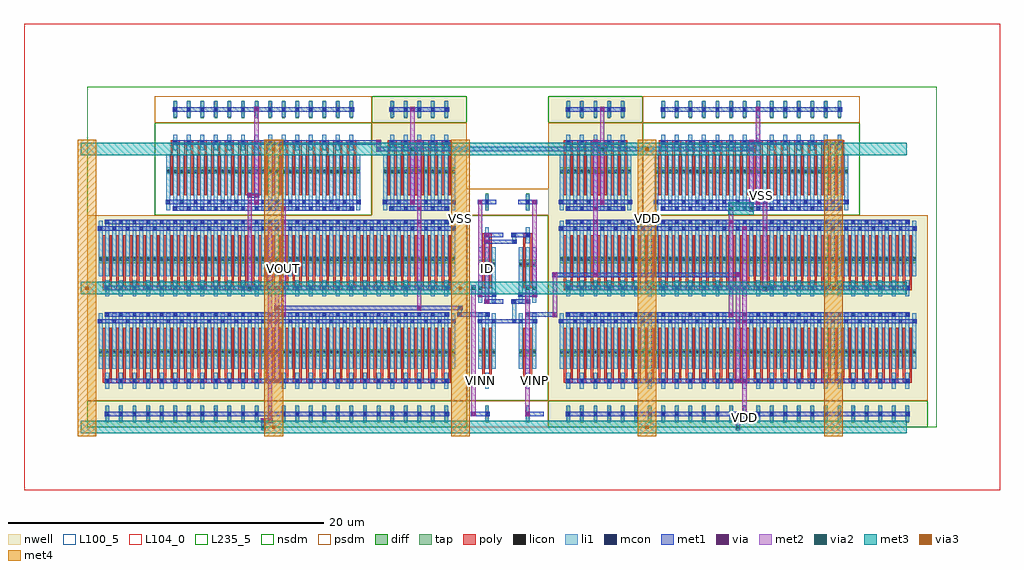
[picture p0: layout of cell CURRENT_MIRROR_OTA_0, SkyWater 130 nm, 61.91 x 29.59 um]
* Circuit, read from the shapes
.subckt CURRENT_MIRROR_OTA_0 ID VDD VINN VINP VOUT VSS
XM1 VOUT n1 VSS VSS sky130_fd_pr__nfet_01v8 w=0.42 l=0.15 m=28
XM2 n2 VINN n3 VSS sky130_fd_pr__nfet_01v8 w=0.42 l=0.15 m=2
XM3 ID ID VSS VSS sky130_fd_pr__nfet_01v8 w=0.42 l=0.15 m=2
XM4 n4 VINP n3 VSS sky130_fd_pr__nfet_01v8 w=0.42 l=0.15 m=2
XM5 n3 ID VSS VSS sky130_fd_pr__nfet_01v8 w=0.42 l=0.15 m=2
XM6 n1 n1 VSS VSS sky130_fd_pr__nfet_01v8 w=0.42 l=0.15 m=28
XM7 VOUT n2 VDD VDD sky130_fd_pr__pfet_01v8 w=0.42 l=0.15 m=104
XM8 n2 n2 VDD VDD sky130_fd_pr__pfet_01v8 w=0.42 l=0.15 m=10
XM9 n1 n4 VDD VDD sky130_fd_pr__pfet_01v8 w=0.42 l=0.15 m=104
XM10 n4 n4 VDD VDD sky130_fd_pr__pfet_01v8 w=0.42 l=0.15 m=10
.ends

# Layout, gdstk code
from math import pi, radians
import gdstk
lib = gdstk.Library(unit=1e-6, precision=1e-09)
def R(c, l, rs):  # rectangles x0, y0, x1, y1
    for r in rs: c.add(gdstk.rectangle(r[:2], r[2:], *l))
def A(c, l, x, y, w, h, nx, ny, dx, dy):  # array of equal rectangles
    R(c, l, [(x+i*dx, y+j*dy, x+i*dx+w, y+j*dy+h) for i in range(nx) for j in range(ny)])
def P(c, l, *ps):  # polygons
    for p in ps: c.add(gdstk.Polygon(p, *l))
nwell = (64, 20)
diff = (65, 20)
tap = (65, 44)
poly = (66, 20)
licon = (66, 44)
li1 = (67, 20)
mcon = (67, 44)
met1 = (68, 20)
via = (68, 44)
met2 = (69, 20)
via2 = (69, 44)
met3 = (70, 20)
via3 = (70, 44)
met4 = (71, 20)
nsdm = (93, 44)
psdm = (94, 20)
L100_5 = (100, 5)
L104_0 = (104, 0)
L235_5 = (235, 5)

dcl_nmos_s_8415993_x1_y1 = lib.new_cell('DCL_NMOS_S_8415993_X1_Y1_1730840086')
R(dcl_nmos_s_8415993_x1_y1, diff, [(0.735,2.625,1.845,3.045)])
R(dcl_nmos_s_8415993_x1_y1, tap, [(1.205,6.16,1.375,7.28)])
R(dcl_nmos_s_8415993_x1_y1, poly, [(1,1.26,1.15,4.62), (1.43,1.26,1.58,4.62), (1,4.485,1.58,4.755)])
A(dcl_nmos_s_8415993_x1_y1, licon, 0.775, 2.705, 0.17, 0.17, 3, 1, 0.43, 0)
R(dcl_nmos_s_8415993_x1_y1, licon, [(1.205,4.535,1.375,4.705), (1.205,6.635,1.375,6.805)])
A(dcl_nmos_s_8415993_x1_y1, li1, 0.735, 0.335, 0.25, 3.53, 3, 1, 0.43, 0)
R(dcl_nmos_s_8415993_x1_y1, li1, [(1.165,4.115,1.415,5.125), (1.165,6.215,1.415,7.225)])
R(dcl_nmos_s_8415993_x1_y1, mcon, [(1.205,0.335,1.375,0.505), (0.775,0.755,0.945,0.925), (1.635,0.755,1.805,0.925), (1.205,4.535,1.375,4.705), (1.205,6.635,1.375,6.805)])
R(dcl_nmos_s_8415993_x1_y1, met1, [(0.26,0.28,1.46,0.56), (0.69,0.7,1.89,0.98), (0.26,4.48,1.46,4.76), (0.69,6.58,1.89,6.86)])
R(dcl_nmos_s_8415993_x1_y1, via, [(1.215,0.345,1.365,0.495), (1.645,0.765,1.795,0.915), (1.215,4.545,1.365,4.695), (1.645,6.645,1.795,6.795)])
R(dcl_nmos_s_8415993_x1_y1, met2, [(1.15,0.26,1.43,4.78), (1.58,0.68,1.86,6.88)])
R(dcl_nmos_s_8415993_x1_y1, nsdm, [(0,0,2.58,5.88)])
R(dcl_nmos_s_8415993_x1_y1, psdm, [(0,5.88,2.58,7.56)])
R(dcl_nmos_s_8415993_x1_y1, L100_5, [(0,0,2.58,7.56)])

dcl_nmos_s_91990922_x14_ = lib.new_cell('DCL_NMOS_S_91990922_X14_Y1_1730840087')
R(dcl_nmos_s_91990922_x14_, diff, [(0.735,2.625,13.025,3.045)])
A(dcl_nmos_s_91990922_x14_, tap, 1.205, 6.16, 0.17, 1.12, 14, 1, 0.86, 0)
A(dcl_nmos_s_91990922_x14_, poly, 1, 1.26, 0.15, 3.36, 28, 1, 0.43, 0)
A(dcl_nmos_s_91990922_x14_, poly, 1, 4.485, 0.58, 0.27, 14, 1, 0.86, 0)
A(dcl_nmos_s_91990922_x14_, licon, 0.775, 2.705, 0.17, 0.17, 3, 1, 0.43, 0)
A(dcl_nmos_s_91990922_x14_, licon, 1.635, 2.705, 0.17, 0.17, 3, 1, 0.43, 0)
A(dcl_nmos_s_91990922_x14_, licon, 2.495, 2.705, 0.17, 0.17, 3, 1, 0.43, 0)
A(dcl_nmos_s_91990922_x14_, licon, 3.355, 2.705, 0.17, 0.17, 3, 1, 0.43, 0)
A(dcl_nmos_s_91990922_x14_, licon, 4.215, 2.705, 0.17, 0.17, 3, 1, 0.43, 0)
A(dcl_nmos_s_91990922_x14_, licon, 5.075, 2.705, 0.17, 0.17, 3, 1, 0.43, 0)
A(dcl_nmos_s_91990922_x14_, licon, 5.935, 2.705, 0.17, 0.17, 3, 1, 0.43, 0)
A(dcl_nmos_s_91990922_x14_, licon, 6.795, 2.705, 0.17, 0.17, 3, 1, 0.43, 0)
A(dcl_nmos_s_91990922_x14_, licon, 7.655, 2.705, 0.17, 0.17, 3, 1, 0.43, 0)
A(dcl_nmos_s_91990922_x14_, licon, 8.515, 2.705, 0.17, 0.17, 3, 1, 0.43, 0)
A(dcl_nmos_s_91990922_x14_, licon, 9.375, 2.705, 0.17, 0.17, 3, 1, 0.43, 0)
A(dcl_nmos_s_91990922_x14_, licon, 10.235, 2.705, 0.17, 0.17, 3, 1, 0.43, 0)
A(dcl_nmos_s_91990922_x14_, licon, 11.095, 2.705, 0.17, 0.17, 3, 1, 0.43, 0)
A(dcl_nmos_s_91990922_x14_, licon, 11.955, 2.705, 0.17, 0.17, 3, 1, 0.43, 0)
A(dcl_nmos_s_91990922_x14_, licon, 1.205, 4.535, 0.17, 0.17, 14, 2, 0.86, 2.1)
A(dcl_nmos_s_91990922_x14_, li1, 0.735, 0.335, 0.25, 3.53, 29, 1, 0.43, 0)
A(dcl_nmos_s_91990922_x14_, li1, 1.165, 4.115, 0.25, 1.01, 14, 2, 0.86, 2.1)
A(dcl_nmos_s_91990922_x14_, mcon, 1.205, 0.335, 0.17, 0.17, 14, 2, 0.86, 4.2)
A(dcl_nmos_s_91990922_x14_, mcon, 0.775, 0.755, 0.17, 0.17, 15, 1, 0.86, 0)
A(dcl_nmos_s_91990922_x14_, mcon, 1.205, 6.635, 0.17, 0.17, 14, 1, 0.86, 0)
R(dcl_nmos_s_91990922_x14_, met1, [(1.12,0.28,12.64,0.56), (0.69,0.7,13.07,0.98), (1.12,4.48,12.64,4.76), (1.12,6.58,12.64,6.86)])
R(dcl_nmos_s_91990922_x14_, via, [(6.805,0.345,6.955,0.495), (7.235,0.765,7.385,0.915), (6.805,4.545,6.955,4.695), (7.235,6.645,7.385,6.795)])
R(dcl_nmos_s_91990922_x14_, met2, [(6.74,0.26,7.02,4.78), (7.17,0.68,7.45,6.88)])
R(dcl_nmos_s_91990922_x14_, nsdm, [(0,0,13.76,5.88)])
R(dcl_nmos_s_91990922_x14_, psdm, [(0,5.88,13.76,7.56)])
R(dcl_nmos_s_91990922_x14_, L100_5, [(0,0,13.76,7.56)])

dcl_pmos_s_18488141_x5_y = lib.new_cell('DCL_PMOS_S_18488141_X5_Y1_1730840088')
R(dcl_pmos_s_18488141_x5_y, nwell, [(0,0,6.02,7.56)])
R(dcl_pmos_s_18488141_x5_y, diff, [(0.735,2.625,5.285,3.045)])
A(dcl_pmos_s_18488141_x5_y, tap, 1.205, 6.16, 0.17, 1.12, 5, 1, 0.86, 0)
A(dcl_pmos_s_18488141_x5_y, poly, 1, 1.26, 0.15, 3.36, 10, 1, 0.43, 0)
A(dcl_pmos_s_18488141_x5_y, poly, 1, 4.485, 0.58, 0.27, 5, 1, 0.86, 0)
A(dcl_pmos_s_18488141_x5_y, licon, 0.775, 2.705, 0.17, 0.17, 3, 1, 0.43, 0)
A(dcl_pmos_s_18488141_x5_y, licon, 1.635, 2.705, 0.17, 0.17, 3, 1, 0.43, 0)
A(dcl_pmos_s_18488141_x5_y, licon, 2.495, 2.705, 0.17, 0.17, 3, 1, 0.43, 0)
A(dcl_pmos_s_18488141_x5_y, licon, 3.355, 2.705, 0.17, 0.17, 3, 1, 0.43, 0)
A(dcl_pmos_s_18488141_x5_y, licon, 4.215, 2.705, 0.17, 0.17, 3, 1, 0.43, 0)
A(dcl_pmos_s_18488141_x5_y, licon, 1.205, 4.535, 0.17, 0.17, 5, 2, 0.86, 2.1)
A(dcl_pmos_s_18488141_x5_y, li1, 0.735, 0.335, 0.25, 3.53, 11, 1, 0.43, 0)
A(dcl_pmos_s_18488141_x5_y, li1, 1.165, 4.115, 0.25, 1.01, 5, 2, 0.86, 2.1)
A(dcl_pmos_s_18488141_x5_y, mcon, 1.205, 0.335, 0.17, 0.17, 5, 2, 0.86, 4.2)
A(dcl_pmos_s_18488141_x5_y, mcon, 0.775, 0.755, 0.17, 0.17, 6, 1, 0.86, 0)
A(dcl_pmos_s_18488141_x5_y, mcon, 1.205, 6.635, 0.17, 0.17, 5, 1, 0.86, 0)
R(dcl_pmos_s_18488141_x5_y, met1, [(1.12,0.28,4.9,0.56), (0.69,0.7,5.33,0.98), (1.12,4.48,4.9,4.76), (1.12,6.58,4.9,6.86)])
R(dcl_pmos_s_18488141_x5_y, via, [(2.935,0.345,3.085,0.495), (3.365,0.765,3.515,0.915), (2.935,4.545,3.085,4.695), (3.365,6.645,3.515,6.795)])
R(dcl_pmos_s_18488141_x5_y, met2, [(2.87,0.26,3.15,4.78), (3.3,0.68,3.58,6.88)])
R(dcl_pmos_s_18488141_x5_y, nsdm, [(0,5.88,6.02,7.56)])
R(dcl_pmos_s_18488141_x5_y, psdm, [(0,0,6.02,5.88)])
R(dcl_pmos_s_18488141_x5_y, L100_5, [(0,0,6.02,7.56)])

nmos_s_70322697_x14_y1_1 = lib.new_cell('NMOS_S_70322697_X14_Y1_1730840090')
R(nmos_s_70322697_x14_y1_1, diff, [(0.735,2.625,13.025,3.045)])
A(nmos_s_70322697_x14_y1_1, tap, 1.205, 6.16, 0.17, 1.12, 14, 1, 0.86, 0)
A(nmos_s_70322697_x14_y1_1, poly, 1, 1.26, 0.15, 3.36, 28, 1, 0.43, 0)
A(nmos_s_70322697_x14_y1_1, poly, 1, 4.485, 0.58, 0.27, 14, 1, 0.86, 0)
A(nmos_s_70322697_x14_y1_1, licon, 0.775, 2.705, 0.17, 0.17, 3, 1, 0.43, 0)
A(nmos_s_70322697_x14_y1_1, licon, 1.635, 2.705, 0.17, 0.17, 3, 1, 0.43, 0)
A(nmos_s_70322697_x14_y1_1, licon, 2.495, 2.705, 0.17, 0.17, 3, 1, 0.43, 0)
A(nmos_s_70322697_x14_y1_1, licon, 3.355, 2.705, 0.17, 0.17, 3, 1, 0.43, 0)
A(nmos_s_70322697_x14_y1_1, licon, 4.215, 2.705, 0.17, 0.17, 3, 1, 0.43, 0)
A(nmos_s_70322697_x14_y1_1, licon, 5.075, 2.705, 0.17, 0.17, 3, 1, 0.43, 0)
A(nmos_s_70322697_x14_y1_1, licon, 5.935, 2.705, 0.17, 0.17, 3, 1, 0.43, 0)
A(nmos_s_70322697_x14_y1_1, licon, 6.795, 2.705, 0.17, 0.17, 3, 1, 0.43, 0)
A(nmos_s_70322697_x14_y1_1, licon, 7.655, 2.705, 0.17, 0.17, 3, 1, 0.43, 0)
A(nmos_s_70322697_x14_y1_1, licon, 8.515, 2.705, 0.17, 0.17, 3, 1, 0.43, 0)
A(nmos_s_70322697_x14_y1_1, licon, 9.375, 2.705, 0.17, 0.17, 3, 1, 0.43, 0)
A(nmos_s_70322697_x14_y1_1, licon, 10.235, 2.705, 0.17, 0.17, 3, 1, 0.43, 0)
A(nmos_s_70322697_x14_y1_1, licon, 11.095, 2.705, 0.17, 0.17, 3, 1, 0.43, 0)
A(nmos_s_70322697_x14_y1_1, licon, 11.955, 2.705, 0.17, 0.17, 3, 1, 0.43, 0)
A(nmos_s_70322697_x14_y1_1, licon, 1.205, 4.535, 0.17, 0.17, 14, 2, 0.86, 2.1)
A(nmos_s_70322697_x14_y1_1, li1, 0.735, 0.335, 0.25, 3.53, 29, 1, 0.43, 0)
A(nmos_s_70322697_x14_y1_1, li1, 1.165, 4.115, 0.25, 1.01, 14, 2, 0.86, 2.1)
A(nmos_s_70322697_x14_y1_1, mcon, 1.205, 0.335, 0.17, 0.17, 14, 2, 0.86, 4.2)
A(nmos_s_70322697_x14_y1_1, mcon, 0.775, 0.755, 0.17, 0.17, 15, 1, 0.86, 0)
A(nmos_s_70322697_x14_y1_1, mcon, 1.205, 6.635, 0.17, 0.17, 14, 1, 0.86, 0)
R(nmos_s_70322697_x14_y1_1, met1, [(1.12,0.28,12.64,0.56), (0.69,0.7,13.07,0.98), (1.12,4.48,12.64,4.76), (1.12,6.58,12.64,6.86)])
R(nmos_s_70322697_x14_y1_1, via, [(7.235,0.765,7.385,0.915), (7.235,6.645,7.385,6.795)])
R(nmos_s_70322697_x14_y1_1, met2, [(7.17,0.68,7.45,6.88)])
R(nmos_s_70322697_x14_y1_1, nsdm, [(0,0,13.76,5.88)])
R(nmos_s_70322697_x14_y1_1, psdm, [(0,5.88,13.76,7.56)])
R(nmos_s_70322697_x14_y1_1, L100_5, [(0,0,13.76,7.56)])

nmos_s_73503000_x1_y1_17 = lib.new_cell('NMOS_S_73503000_X1_Y1_1730840091')
R(nmos_s_73503000_x1_y1_17, diff, [(0.735,2.625,1.845,3.045)])
R(nmos_s_73503000_x1_y1_17, tap, [(1.205,6.16,1.375,7.28)])
R(nmos_s_73503000_x1_y1_17, poly, [(1,1.26,1.15,4.62), (1.43,1.26,1.58,4.62), (1,4.485,1.58,4.755)])
A(nmos_s_73503000_x1_y1_17, licon, 0.775, 2.705, 0.17, 0.17, 3, 1, 0.43, 0)
R(nmos_s_73503000_x1_y1_17, licon, [(1.205,4.535,1.375,4.705), (1.205,6.635,1.375,6.805)])
A(nmos_s_73503000_x1_y1_17, li1, 0.735, 0.335, 0.25, 3.53, 3, 1, 0.43, 0)
R(nmos_s_73503000_x1_y1_17, li1, [(1.165,4.115,1.415,5.125), (1.165,6.215,1.415,7.225)])
R(nmos_s_73503000_x1_y1_17, mcon, [(1.205,0.335,1.375,0.505), (0.775,0.755,0.945,0.925), (1.635,0.755,1.805,0.925), (1.205,4.535,1.375,4.705), (1.205,6.635,1.375,6.805)])
R(nmos_s_73503000_x1_y1_17, met1, [(0.26,0.28,1.46,0.56), (0.69,0.7,1.89,0.98), (0.26,4.48,1.46,4.76), (0.69,6.58,1.89,6.86)])
R(nmos_s_73503000_x1_y1_17, via, [(1.645,0.765,1.795,0.915), (1.645,6.645,1.795,6.795)])
R(nmos_s_73503000_x1_y1_17, met2, [(1.58,0.68,1.86,6.88)])
R(nmos_s_73503000_x1_y1_17, nsdm, [(0,0,2.58,5.88)])
R(nmos_s_73503000_x1_y1_17, psdm, [(0,5.88,2.58,7.56)])
R(nmos_s_73503000_x1_y1_17, L100_5, [(0,0,2.58,7.56)])

pmos_s_55784090_x26_y2_1 = lib.new_cell('PMOS_S_55784090_X26_Y2_1730840092')
R(pmos_s_55784090_x26_y2_1, nwell, [(0,0,24.08,13.44)])
R(pmos_s_55784090_x26_y2_1, diff, [(0.735,2.625,23.345,3.045), (0.735,8.505,23.345,8.925)])
A(pmos_s_55784090_x26_y2_1, tap, 1.205, 12.04, 0.17, 1.12, 26, 1, 0.86, 0)
A(pmos_s_55784090_x26_y2_1, poly, 1, 1.26, 0.15, 3.36, 52, 2, 0.43, 5.88)
A(pmos_s_55784090_x26_y2_1, poly, 1, 4.485, 0.58, 0.27, 26, 2, 0.86, 5.88)
A(pmos_s_55784090_x26_y2_1, licon, 0.775, 2.705, 0.17, 0.17, 3, 2, 0.43, 5.88)
A(pmos_s_55784090_x26_y2_1, licon, 1.635, 2.705, 0.17, 0.17, 3, 2, 0.43, 5.88)
A(pmos_s_55784090_x26_y2_1, licon, 2.495, 2.705, 0.17, 0.17, 3, 2, 0.43, 5.88)
A(pmos_s_55784090_x26_y2_1, licon, 3.355, 2.705, 0.17, 0.17, 3, 2, 0.43, 5.88)
A(pmos_s_55784090_x26_y2_1, licon, 4.215, 2.705, 0.17, 0.17, 3, 2, 0.43, 5.88)
A(pmos_s_55784090_x26_y2_1, licon, 5.075, 2.705, 0.17, 0.17, 3, 2, 0.43, 5.88)
A(pmos_s_55784090_x26_y2_1, licon, 5.935, 2.705, 0.17, 0.17, 3, 2, 0.43, 5.88)
A(pmos_s_55784090_x26_y2_1, licon, 6.795, 2.705, 0.17, 0.17, 3, 2, 0.43, 5.88)
A(pmos_s_55784090_x26_y2_1, licon, 7.655, 2.705, 0.17, 0.17, 3, 2, 0.43, 5.88)
A(pmos_s_55784090_x26_y2_1, licon, 8.515, 2.705, 0.17, 0.17, 3, 2, 0.43, 5.88)
A(pmos_s_55784090_x26_y2_1, licon, 9.375, 2.705, 0.17, 0.17, 3, 2, 0.43, 5.88)
A(pmos_s_55784090_x26_y2_1, licon, 10.235, 2.705, 0.17, 0.17, 3, 2, 0.43, 5.88)
A(pmos_s_55784090_x26_y2_1, licon, 11.095, 2.705, 0.17, 0.17, 3, 2, 0.43, 5.88)
A(pmos_s_55784090_x26_y2_1, licon, 11.955, 2.705, 0.17, 0.17, 3, 2, 0.43, 5.88)
A(pmos_s_55784090_x26_y2_1, licon, 12.815, 2.705, 0.17, 0.17, 3, 2, 0.43, 5.88)
A(pmos_s_55784090_x26_y2_1, licon, 13.675, 2.705, 0.17, 0.17, 3, 2, 0.43, 5.88)
A(pmos_s_55784090_x26_y2_1, licon, 14.535, 2.705, 0.17, 0.17, 3, 2, 0.43, 5.88)
A(pmos_s_55784090_x26_y2_1, licon, 15.395, 2.705, 0.17, 0.17, 3, 2, 0.43, 5.88)
A(pmos_s_55784090_x26_y2_1, licon, 16.255, 2.705, 0.17, 0.17, 3, 2, 0.43, 5.88)
A(pmos_s_55784090_x26_y2_1, licon, 17.115, 2.705, 0.17, 0.17, 3, 2, 0.43, 5.88)
A(pmos_s_55784090_x26_y2_1, licon, 17.975, 2.705, 0.17, 0.17, 3, 2, 0.43, 5.88)
A(pmos_s_55784090_x26_y2_1, licon, 18.835, 2.705, 0.17, 0.17, 3, 2, 0.43, 5.88)
A(pmos_s_55784090_x26_y2_1, licon, 19.695, 2.705, 0.17, 0.17, 3, 2, 0.43, 5.88)
A(pmos_s_55784090_x26_y2_1, licon, 20.555, 2.705, 0.17, 0.17, 3, 2, 0.43, 5.88)
A(pmos_s_55784090_x26_y2_1, licon, 21.415, 2.705, 0.17, 0.17, 3, 2, 0.43, 5.88)
A(pmos_s_55784090_x26_y2_1, licon, 22.275, 2.705, 0.17, 0.17, 3, 2, 0.43, 5.88)
A(pmos_s_55784090_x26_y2_1, licon, 1.205, 4.535, 0.17, 0.17, 26, 2, 0.86, 5.88)
R(pmos_s_55784090_x26_y2_1, licon, [(1.205,12.515,1.375,12.685), (1.205,12.515,1.375,12.685), (2.065,12.515,2.235,12.685), (2.065,12.515,2.235,12.685), (2.925,12.515,3.095,12.685), (2.925,12.515,3.095,12.685), (3.785,12.515,3.955,12.685), (3.785,12.515,3.955,12.685), (4.645,12.515,4.815,12.685), (4.645,12.515,4.815,12.685), (5.505,12.515,5.675,12.685), (5.505,12.515,5.675,12.685), (6.365,12.515,6.535,12.685), (6.365,12.515,6.535,12.685), (7.225,12.515,7.395,12.685), (7.225,12.515,7.395,12.685), (8.085,12.515,8.255,12.685), (8.085,12.515,8.255,12.685), (8.945,12.515,9.115,12.685), (8.945,12.515,9.115,12.685), (9.805,12.515,9.975,12.685), (9.805,12.515,9.975,12.685), (10.665,12.515,10.835,12.685), (10.665,12.515,10.835,12.685), (11.525,12.515,11.695,12.685), (11.525,12.515,11.695,12.685), (12.385,12.515,12.555,12.685), (12.385,12.515,12.555,12.685), (13.245,12.515,13.415,12.685), (13.245,12.515,13.415,12.685), (14.105,12.515,14.275,12.685), (14.105,12.515,14.275,12.685), (14.965,12.515,15.135,12.685), (14.965,12.515,15.135,12.685), (15.825,12.515,15.995,12.685), (15.825,12.515,15.995,12.685), (16.685,12.515,16.855,12.685), (16.685,12.515,16.855,12.685), (17.545,12.515,17.715,12.685), (17.545,12.515,17.715,12.685), (18.405,12.515,18.575,12.685), (18.405,12.515,18.575,12.685), (19.265,12.515,19.435,12.685), (19.265,12.515,19.435,12.685), (20.125,12.515,20.295,12.685), (20.125,12.515,20.295,12.685), (20.985,12.515,21.155,12.685), (20.985,12.515,21.155,12.685), (21.845,12.515,22.015,12.685), (21.845,12.515,22.015,12.685), (22.705,12.515,22.875,12.685), (22.705,12.515,22.875,12.685)])
A(pmos_s_55784090_x26_y2_1, li1, 0.735, 0.335, 0.25, 3.53, 53, 2, 0.43, 5.88)
A(pmos_s_55784090_x26_y2_1, li1, 1.165, 4.115, 0.25, 1.01, 26, 2, 0.86, 5.88)
A(pmos_s_55784090_x26_y2_1, li1, 1.165, 12.095, 0.25, 1.01, 26, 1, 0.86, 0)
A(pmos_s_55784090_x26_y2_1, mcon, 1.205, 0.335, 0.17, 0.17, 26, 2, 0.86, 4.2)
A(pmos_s_55784090_x26_y2_1, mcon, 0.775, 0.755, 0.17, 0.17, 27, 2, 0.86, 5.88)
A(pmos_s_55784090_x26_y2_1, mcon, 1.205, 6.215, 0.17, 0.17, 26, 2, 0.86, 4.2)
A(pmos_s_55784090_x26_y2_1, mcon, 1.205, 12.515, 0.17, 0.17, 26, 1, 0.86, 0)
R(pmos_s_55784090_x26_y2_1, met1, [(1.12,0.28,22.96,0.56), (0.69,0.7,23.39,0.98), (1.12,4.48,22.96,4.76), (1.12,6.16,22.96,6.44), (0.69,6.58,23.39,6.86), (1.12,10.36,22.96,10.64), (1.12,12.46,22.96,12.74)])
A(pmos_s_55784090_x26_y2_1, via, 12.395, 0.765, 0.15, 0.15, 1, 3, 0, 5.88)
R(pmos_s_55784090_x26_y2_1, via, [(11.535,0.345,11.685,0.495), (11.965,4.545,12.115,4.695), (11.535,6.225,11.685,6.375), (11.965,10.425,12.115,10.575)])
R(pmos_s_55784090_x26_y2_1, met2, [(11.47,0.26,11.75,6.46), (12.33,0.68,12.61,12.76), (11.9,4.46,12.18,10.66)])
R(pmos_s_55784090_x26_y2_1, nsdm, [(0,11.76,24.08,13.44)])
R(pmos_s_55784090_x26_y2_1, psdm, [(0,0,24.08,11.76)])
R(pmos_s_55784090_x26_y2_1, L100_5, [(0,0,24.08,13.44)])

nmos_4t_9061234_x1_y1_17 = lib.new_cell('NMOS_4T_9061234_X1_Y1_1730840089')
R(nmos_4t_9061234_x1_y1_17, diff, [(0.735,2.625,1.845,3.045)])
R(nmos_4t_9061234_x1_y1_17, tap, [(1.205,6.16,1.375,7.28)])
R(nmos_4t_9061234_x1_y1_17, poly, [(1,1.26,1.15,4.62), (1.43,1.26,1.58,4.62), (1,4.485,1.58,4.755)])
A(nmos_4t_9061234_x1_y1_17, licon, 0.775, 2.705, 0.17, 0.17, 3, 1, 0.43, 0)
R(nmos_4t_9061234_x1_y1_17, licon, [(1.205,4.535,1.375,4.705), (1.205,6.635,1.375,6.805)])
A(nmos_4t_9061234_x1_y1_17, li1, 0.735, 0.335, 0.25, 3.53, 3, 1, 0.43, 0)
R(nmos_4t_9061234_x1_y1_17, li1, [(1.165,4.115,1.415,5.125), (1.165,6.215,1.415,7.225)])
R(nmos_4t_9061234_x1_y1_17, mcon, [(1.205,0.335,1.375,0.505), (0.775,0.755,0.945,0.925), (1.635,0.755,1.805,0.925), (1.205,4.535,1.375,4.705), (1.205,6.635,1.375,6.805)])
R(nmos_4t_9061234_x1_y1_17, met1, [(0.26,0.28,1.46,0.56), (0.69,0.7,1.89,0.98), (0.26,4.48,1.46,4.76), (0.26,6.58,1.46,6.86)])
R(nmos_4t_9061234_x1_y1_17, nsdm, [(0,0,2.58,5.88)])
R(nmos_4t_9061234_x1_y1_17, psdm, [(0,5.88,2.58,7.56)])
R(nmos_4t_9061234_x1_y1_17, L100_5, [(0,0,2.58,7.56)])

current_mirror_ota_0 = lib.new_cell('CURRENT_MIRROR_OTA_0')
R(current_mirror_ota_0, li1, [(26.965,6.635,27.215,6.805), (26.965,6.635,27.215,6.805), (26.965,6.72,27.215,7.98), (23.525,7.055,23.775,7.225), (23.525,7.055,23.775,7.225), (23.525,7.055,23.775,7.225), (23.525,7.055,23.775,7.225), (23.525,7.14,23.775,7.56), (23.525,7.475,23.775,7.645), (23.525,7.475,23.775,7.645), (23.525,7.475,23.775,7.645), (23.525,7.475,23.775,7.645), (26.965,7.895,27.215,8.065), (26.965,7.895,27.215,8.065), (26.965,11.675,27.215,11.845), (26.965,11.675,27.215,11.845), (26.965,11.76,27.215,12.18), (26.965,12.095,27.215,12.265), (26.965,12.095,27.215,12.265)])
R(current_mirror_ota_0, mcon, [(27.005,6.635,27.175,6.805), (27.005,6.635,27.175,6.805), (23.565,7.055,23.735,7.225), (23.565,7.055,23.735,7.225), (23.565,7.055,23.735,7.225), (23.565,7.055,23.735,7.225), (23.565,7.475,23.735,7.645), (23.565,7.475,23.735,7.645), (23.565,7.475,23.735,7.645), (23.565,7.475,23.735,7.645), (27.005,7.895,27.175,8.065), (27.005,7.895,27.175,8.065), (27.005,11.675,27.175,11.845), (27.005,11.675,27.175,11.845), (27.005,12.095,27.175,12.265), (27.005,12.095,27.175,12.265)])
R(current_mirror_ota_0, met1, [(11.02,0.28,11.34,0.56), (11.02,0.28,11.34,0.56), (11.18,0.28,11.61,0.56), (11.45,0.28,11.77,0.56), (11.45,0.28,11.77,0.56), (41.12,0.28,41.44,0.56), (41.12,0.28,41.44,0.56), (41.12,0.28,41.44,0.56), (41.28,0.28,41.71,0.56), (41.55,0.28,41.87,0.56), (41.55,0.28,41.87,0.56), (41.55,0.28,41.87,0.56), (24.35,0.7,24.67,0.98), (24.35,0.7,24.67,0.98), (24.35,0.7,24.67,0.98), (27.79,0.7,28.11,0.98), (27.79,0.7,28.11,0.98), (25.8,6.58,27.52,6.86), (26.92,6.58,27.26,6.86), (26.92,6.58,27.26,6.86), (23.48,7,23.82,7.28), (23.48,7,23.82,7.28), (23.48,7,23.82,7.28), (23.48,7,23.82,7.28), (23.65,7,24.51,7.28), (28.81,7,29.67,7.28), (29.51,7,29.83,7.28), (29.51,7,29.83,7.28), (29.51,7,29.83,7.28), (29.51,7,29.83,7.28), (11.88,7.42,12.2,7.7), (11.88,7.42,12.2,7.7), (11.88,7.42,12.2,7.7), (11.88,7.42,12.2,7.7), (12.04,7.42,23.65,7.7), (20.91,7.42,21.23,7.7), (20.91,7.42,21.23,7.7), (23.48,7.42,23.82,7.7), (23.48,7.42,23.82,7.7), (23.48,7.42,23.82,7.7), (23.48,7.42,23.82,7.7), (26.92,7.84,27.26,8.12), (26.92,7.84,27.26,8.12), (29.51,9.52,29.83,9.8), (29.51,9.52,29.83,9.8), (29.51,9.52,29.83,9.8), (29.51,9.52,29.83,9.8), (29.67,9.52,32.25,9.8), (32.09,9.52,32.41,9.8), (32.09,9.52,32.41,9.8), (32.09,9.52,32.41,9.8), (32.09,9.52,32.41,9.8), (32.25,9.52,41.28,9.8), (41.12,9.52,41.44,9.8), (41.12,9.52,41.44,9.8), (25.21,11.62,25.53,11.9), (25.21,11.62,25.53,11.9), (25.37,11.62,27.09,11.9), (26.92,11.62,27.26,11.9), (26.92,11.62,27.26,11.9), (26.92,12.04,27.26,12.32), (26.92,12.04,27.26,12.32), (12.31,13.72,12.63,14), (12.31,13.72,12.63,14), (10.16,14.56,10.48,14.84), (10.16,14.56,10.48,14.84), (10.16,14.56,10.48,14.84), (10.16,14.56,10.48,14.84), (10.16,14.56,10.48,14.84), (10.32,14.56,10.75,14.84), (10.59,14.56,10.91,14.84), (10.59,14.56,10.91,14.84), (10.59,14.56,10.91,14.84), (10.59,14.56,10.91,14.84), (10.59,14.56,10.91,14.84), (42.41,14.56,42.73,14.84), (42.41,14.56,42.73,14.84), (42.41,14.56,42.73,14.84), (42.41,14.56,42.73,14.84), (42.41,14.56,42.73,14.84), (42.41,14.56,42.73,14.84), (42.57,14.56,43,14.84), (42.84,14.56,43.16,14.84), (42.84,14.56,43.16,14.84), (42.84,14.56,43.16,14.84), (42.84,14.56,43.16,14.84), (42.84,14.56,43.16,14.84), (42.84,14.56,43.16,14.84), (18.33,17.5,18.65,17.78), (18.33,17.5,18.65,17.78), (18.33,17.5,18.65,17.78), (18.33,17.5,18.65,17.78), (18.49,17.5,42.14,17.78), (41.98,17.5,42.3,17.78), (41.98,17.5,42.3,17.78), (41.98,17.5,42.3,17.78), (41.98,17.5,42.3,17.78), (16.77,17.92,18.49,18.2), (18.33,17.92,18.65,18.2), (18.33,17.92,18.65,18.2), (18.33,17.92,18.65,18.2), (18.33,17.92,18.65,18.2)])
P(current_mirror_ota_0, met1, [(0,0),(0,0),(0,0),(0,0)],
  [(0,0),(0,0),(0,0),(0,0)],
  [(0,0),(0,0),(0,0),(0,0)],
  [(0,0),(0,0),(0,0),(0,0)],
  [(0,0),(0,0),(0,0),(0,0)],
  [(0,0),(0,0),(0,0),(0,0)],
  [(0,0),(0,0),(0,0),(0,0)],
  [(0,0),(0,0),(0,0),(0,0)],
  [(0,0),(0,0),(0,0),(0,0)],
  [(0,0),(0,0),(0,0),(0,0)],
  [(0,0),(0,0),(0,0),(0,0)],
  [(0,0),(0,0),(0,0),(0,0)],
  [(0,0),(0,0),(0,0),(0,0)],
  [(0,0),(0,0),(0,0),(0,0)])
R(current_mirror_ota_0, via, [(11.105,0.345,11.255,0.495), (11.105,0.345,11.255,0.495), (11.535,0.345,11.685,0.495), (11.535,0.345,11.685,0.495), (41.205,0.345,41.355,0.495), (41.205,0.345,41.355,0.495), (41.205,0.345,41.355,0.495), (41.635,0.345,41.785,0.495), (41.635,0.345,41.785,0.495), (41.635,0.345,41.785,0.495), (24.435,0.765,24.585,0.915), (24.435,0.765,24.585,0.915), (24.435,0.765,24.585,0.915), (27.875,0.765,28.025,0.915), (27.875,0.765,28.025,0.915), (29.595,7.065,29.745,7.215), (29.595,7.065,29.745,7.215), (29.595,7.065,29.745,7.215), (29.595,7.065,29.745,7.215), (11.965,7.485,12.115,7.635), (11.965,7.485,12.115,7.635), (11.965,7.485,12.115,7.635), (11.965,7.485,12.115,7.635), (20.995,7.485,21.145,7.635), (20.995,7.485,21.145,7.635), (29.595,9.585,29.745,9.735), (29.595,9.585,29.745,9.735), (29.595,9.585,29.745,9.735), (29.595,9.585,29.745,9.735), (32.175,9.585,32.325,9.735), (32.175,9.585,32.325,9.735), (32.175,9.585,32.325,9.735), (32.175,9.585,32.325,9.735), (41.205,9.585,41.355,9.735), (41.205,9.585,41.355,9.735), (25.295,11.685,25.445,11.835), (25.295,11.685,25.445,11.835), (12.395,13.785,12.545,13.935), (12.395,13.785,12.545,13.935), (10.245,14.625,10.395,14.775), (10.245,14.625,10.395,14.775), (10.245,14.625,10.395,14.775), (10.245,14.625,10.395,14.775), (10.245,14.625,10.395,14.775), (10.675,14.625,10.825,14.775), (10.675,14.625,10.825,14.775), (10.675,14.625,10.825,14.775), (10.675,14.625,10.825,14.775), (10.675,14.625,10.825,14.775), (42.495,14.625,42.645,14.775), (42.495,14.625,42.645,14.775), (42.495,14.625,42.645,14.775), (42.495,14.625,42.645,14.775), (42.495,14.625,42.645,14.775), (42.495,14.625,42.645,14.775), (42.925,14.625,43.075,14.775), (42.925,14.625,43.075,14.775), (42.925,14.625,43.075,14.775), (42.925,14.625,43.075,14.775), (42.925,14.625,43.075,14.775), (42.925,14.625,43.075,14.775), (18.415,17.565,18.565,17.715), (18.415,17.565,18.565,17.715), (18.415,17.565,18.565,17.715), (18.415,17.565,18.565,17.715), (42.065,17.565,42.215,17.715), (42.065,17.565,42.215,17.715), (42.065,17.565,42.215,17.715), (42.065,17.565,42.215,17.715), (18.415,17.985,18.565,18.135), (18.415,17.985,18.565,18.135), (18.415,17.985,18.565,18.135), (18.415,17.985,18.565,18.135)])
R(current_mirror_ota_0, met2, [(11.04,-0.185,11.32,0.185), (11.04,-0.185,11.32,0.185), (41.14,-0.185,41.42,0.185), (41.14,-0.185,41.42,0.185), (41.14,-0.185,41.42,0.185), (11.04,0,11.32,0.42), (41.14,0,41.42,0.42), (11.04,0.26,11.32,0.58), (11.04,0.26,11.32,0.58), (11.47,0.26,11.75,0.58), (11.47,0.26,11.75,0.58), (41.14,0.26,41.42,0.58), (41.14,0.26,41.42,0.58), (41.14,0.26,41.42,0.58), (41.57,0.26,41.85,0.58), (41.57,0.26,41.85,0.58), (41.57,0.26,41.85,0.58), (11.47,0.42,11.75,0.84), (41.57,0.42,41.85,0.84), (24.37,0.68,24.65,1), (24.37,0.68,24.65,1), (24.37,0.68,24.65,1), (27.81,0.68,28.09,1), (27.81,0.68,28.09,1), (24.37,0.84,24.65,8.82), (27.81,0.84,28.09,8.82), (29.53,6.98,29.81,7.3), (29.53,6.98,29.81,7.3), (29.53,6.98,29.81,7.3), (29.53,6.98,29.81,7.3), (29.53,7.14,29.81,9.66), (11.9,7.4,12.18,7.72), (11.9,7.4,12.18,7.72), (11.9,7.4,12.18,7.72), (11.9,7.4,12.18,7.72), (20.93,7.4,21.21,7.72), (20.93,7.4,21.21,7.72), (20.93,7.56,21.21,13.86), (10.18,8.635,10.46,9.005), (10.18,8.635,10.46,9.005), (10.18,8.635,10.46,9.005), (10.18,8.635,10.46,9.005), (10.18,8.635,10.46,9.005), (24.37,8.635,24.65,9.005), (24.37,8.635,24.65,9.005), (24.37,8.635,24.65,9.005), (24.8,8.635,25.08,9.005), (24.8,8.635,25.08,9.005), (24.8,8.635,25.08,9.005), (24.8,8.635,25.08,9.005), (24.8,8.635,25.08,9.005), (24.8,8.635,25.08,9.005), (24.8,8.635,25.08,9.005), (27.81,8.635,28.09,9.005), (27.81,8.635,28.09,9.005), (28.24,8.635,28.52,9.005), (28.24,8.635,28.52,9.005), (28.24,8.635,28.52,9.005), (28.24,8.635,28.52,9.005), (42.86,8.635,43.14,9.005), (42.86,8.635,43.14,9.005), (42.86,8.635,43.14,9.005), (42.86,8.635,43.14,9.005), (42.86,8.635,43.14,9.005), (42.86,8.635,43.14,9.005), (10.18,8.82,10.46,14.7), (41.14,8.82,41.42,9.66), (42.86,8.82,43.14,14.7), (29.53,9.5,29.81,9.82), (29.53,9.5,29.81,9.82), (29.53,9.5,29.81,9.82), (29.53,9.5,29.81,9.82), (32.11,9.5,32.39,9.82), (32.11,9.5,32.39,9.82), (32.11,9.5,32.39,9.82), (32.11,9.5,32.39,9.82), (41.14,9.5,41.42,9.82), (41.14,9.5,41.42,9.82), (32.11,9.66,32.39,13.86), (25.23,11.6,25.51,11.92), (25.23,11.6,25.51,11.92), (12.33,13.02,12.61,13.86), (40.71,13.02,40.99,13.86), (40.71,13.675,40.99,14.045), (40.71,13.675,40.99,14.045), (42,13.675,42.28,14.045), (42,13.675,42.28,14.045), (12.33,13.7,12.61,14.02), (12.33,13.7,12.61,14.02), (10.18,14.54,10.46,14.86), (10.18,14.54,10.46,14.86), (10.18,14.54,10.46,14.86), (10.18,14.54,10.46,14.86), (10.18,14.54,10.46,14.86), (10.61,14.54,10.89,14.86), (10.61,14.54,10.89,14.86), (10.61,14.54,10.89,14.86), (10.61,14.54,10.89,14.86), (10.61,14.54,10.89,14.86), (42.43,14.54,42.71,14.86), (42.43,14.54,42.71,14.86), (42.43,14.54,42.71,14.86), (42.43,14.54,42.71,14.86), (42.43,14.54,42.71,14.86), (42.43,14.54,42.71,14.86), (42.86,14.54,43.14,14.86), (42.86,14.54,43.14,14.86), (42.86,14.54,43.14,14.86), (42.86,14.54,43.14,14.86), (42.86,14.54,43.14,14.86), (42.86,14.54,43.14,14.86), (20.5,17.455,20.78,17.825), (20.5,17.455,20.78,17.825), (20.5,17.455,20.78,17.825), (20.5,17.455,20.78,17.825), (20.5,17.455,20.78,17.825), (32.54,17.455,32.82,17.825), (32.54,17.455,32.82,17.825), (32.54,17.455,32.82,17.825), (32.54,17.455,32.82,17.825), (18.35,17.48,18.63,17.8), (18.35,17.48,18.63,17.8), (18.35,17.48,18.63,17.8), (18.35,17.48,18.63,17.8), (42,17.48,42.28,17.8), (42,17.48,42.28,17.8), (42,17.48,42.28,17.8), (42,17.48,42.28,17.8), (18.35,17.64,18.63,18.06), (18.35,17.9,18.63,18.22), (18.35,17.9,18.63,18.22), (18.35,17.9,18.63,18.22), (18.35,17.9,18.63,18.22)])
P(current_mirror_ota_0, met2, [(0,0),(0,0),(0,0),(0,0)],
  [(0,0),(0,0),(0,0),(0,0)],
  [(0,0),(0,0),(0,0),(0,0)],
  [(0,0),(0,0),(0,0),(0,0)],
  [(0,0),(0,0),(0,0),(0,0)],
  [(0,0),(0,0),(0,0),(0,0)],
  [(0,0),(0,0),(0,0),(0,0)],
  [(0,0),(0,0),(0,0),(0,0)],
  [(0,0),(0,0),(0,0),(0,0)],
  [(0,0),(0,0),(0,0),(0,0)],
  [(0,0),(0,0),(0,0),(0,0)],
  [(0,0),(0,0),(0,0),(0,0)],
  [(0,0),(0,0),(0,0),(0,0)],
  [(0,0),(0,0),(0,0),(0,0)],
  [(0,0),(0,0),(0,0),(0,0)],
  [(0,0),(0,0),(0,0),(0,0)],
  [(0,0),(0,0),(0,0),(0,0)],
  [(0,0),(0,0),(0,0),(0,0)])
R(current_mirror_ota_0, via2, [(11.08,-0.1,11.28,0.1), (11.08,-0.1,11.28,0.1), (41.18,-0.1,41.38,0.1), (41.18,-0.1,41.38,0.1), (41.18,-0.1,41.38,0.1), (10.22,8.72,10.42,8.92), (10.22,8.72,10.42,8.92), (10.22,8.72,10.42,8.92), (10.22,8.72,10.42,8.92), (10.22,8.72,10.42,8.92), (24.41,8.72,24.61,8.92), (24.41,8.72,24.61,8.92), (24.41,8.72,24.61,8.92), (24.84,8.72,25.04,8.92), (24.84,8.72,25.04,8.92), (24.84,8.72,25.04,8.92), (24.84,8.72,25.04,8.92), (24.84,8.72,25.04,8.92), (24.84,8.72,25.04,8.92), (24.84,8.72,25.04,8.92), (27.85,8.72,28.05,8.92), (27.85,8.72,28.05,8.92), (28.28,8.72,28.48,8.92), (28.28,8.72,28.48,8.92), (28.28,8.72,28.48,8.92), (28.28,8.72,28.48,8.92), (42.9,8.72,43.1,8.92), (42.9,8.72,43.1,8.92), (42.9,8.72,43.1,8.92), (42.9,8.72,43.1,8.92), (42.9,8.72,43.1,8.92), (42.9,8.72,43.1,8.92), (40.75,13.76,40.95,13.96), (40.75,13.76,40.95,13.96), (42.04,13.76,42.24,13.96), (42.04,13.76,42.24,13.96), (20.54,17.54,20.74,17.74), (20.54,17.54,20.74,17.74), (20.54,17.54,20.74,17.74), (20.54,17.54,20.74,17.74), (20.54,17.54,20.74,17.74), (32.58,17.54,32.78,17.74), (32.58,17.54,32.78,17.74), (32.58,17.54,32.78,17.74), (32.58,17.54,32.78,17.74)])
A(current_mirror_ota_0, met3, -0.4, -0.4, 4.24, 0.8, 3, 3, 3.44, 8.82)
A(current_mirror_ota_0, met3, 9.92, -0.4, 2.32, 0.8, 1, 3, 0, 8.82)
A(current_mirror_ota_0, met3, 11.44, -0.4, 2.72, 0.8, 1, 3, 0, 8.82)
A(current_mirror_ota_0, met3, 13.36, -0.4, 4.24, 0.8, 1, 3, 0, 8.82)
A(current_mirror_ota_0, met3, 16.8, -0.4, 4.24, 0.8, 1, 3, 0, 8.82)
A(current_mirror_ota_0, met3, 20.24, -0.4, 3.84, 0.8, 1, 3, 0, 8.82)
A(current_mirror_ota_0, met3, 23.28, -0.4, 1.2, 0.8, 1, 3, 0, 8.82)
A(current_mirror_ota_0, met3, 23.68, -0.4, 4.24, 0.8, 3, 3, 3.44, 8.82)
A(current_mirror_ota_0, met3, 34, -0.4, 1.92, 0.8, 1, 3, 0, 8.82)
A(current_mirror_ota_0, met3, 35.12, -0.4, 3.12, 0.8, 1, 3, 0, 8.82)
A(current_mirror_ota_0, met3, 37.44, -0.4, 4.24, 0.8, 1, 3, 0, 8.82)
A(current_mirror_ota_0, met3, 40.88, -0.4, 4.24, 0.8, 1, 3, 0, 8.82)
A(current_mirror_ota_0, met3, 44.32, -0.4, 3.44, 0.8, 1, 3, 0, 8.82)
A(current_mirror_ota_0, met3, 46.96, -0.4, 1.6, 0.8, 1, 3, 0, 8.82)
A(current_mirror_ota_0, met3, 47.76, -0.4, 4.24, 0.8, 1, 3, 0, 8.82)
R(current_mirror_ota_0, met3, [(11.015,-0.4,11.345,0.4), (11.015,-0.4,11.345,0.4), (11.675,-0.4,12.005,0.4), (35.355,-0.4,35.685,0.4), (41.115,-0.4,41.445,0.4), (41.115,-0.4,41.445,0.4), (41.115,-0.4,41.445,0.4), (-0.165,8.42,0.165,9.22), (10.155,8.42,10.485,9.22), (10.155,8.42,10.485,9.22), (10.155,8.42,10.485,9.22), (10.155,8.42,10.485,9.22), (10.155,8.42,10.485,9.22), (23.515,8.42,23.845,9.22), (24.345,8.42,24.675,9.22), (24.345,8.42,24.675,9.22), (24.345,8.42,24.675,9.22), (24.775,8.42,25.105,9.22), (24.775,8.42,25.105,9.22), (24.775,8.42,25.105,9.22), (24.775,8.42,25.105,9.22), (24.775,8.42,25.105,9.22), (24.775,8.42,25.105,9.22), (24.775,8.42,25.105,9.22), (27.785,8.42,28.115,9.22), (27.785,8.42,28.115,9.22), (28.215,8.42,28.545,9.22), (28.215,8.42,28.545,9.22), (28.215,8.42,28.545,9.22), (28.215,8.42,28.545,9.22), (42.835,8.42,43.165,9.22), (42.835,8.42,43.165,9.22), (42.835,8.42,43.165,9.22), (42.835,8.42,43.165,9.22), (42.835,8.42,43.165,9.22), (42.835,8.42,43.165,9.22), (47.195,8.42,47.525,9.22), (40.685,13.46,41.015,14.26), (40.685,13.46,41.015,14.26), (40.85,13.46,42.14,14.26), (41.975,13.46,42.305,14.26), (41.975,13.46,42.305,14.26), (11.675,17.24,12.005,18.04), (20.475,17.24,20.805,18.04), (20.475,17.24,20.805,18.04), (20.475,17.24,20.805,18.04), (20.475,17.24,20.805,18.04), (20.475,17.24,20.805,18.04), (32.515,17.24,32.845,18.04), (32.515,17.24,32.845,18.04), (32.515,17.24,32.845,18.04), (32.515,17.24,32.845,18.04), (35.355,17.24,35.685,18.04)])
A(current_mirror_ota_0, via3, -0.1, 8.72, 0.2, 0.2, 3, 1, 23.68, 0)
R(current_mirror_ota_0, via3, [(11.74,-0.1,11.94,0.1), (35.42,-0.1,35.62,0.1), (11.74,17.54,11.94,17.74), (35.42,17.54,35.62,17.74)])
A(current_mirror_ota_0, met4, -0.59, -0.59, 1.18, 10, 5, 2, 11.84, 8.82)
A(current_mirror_ota_0, met4, -0.59, 8.655, 1.18, 0.33, 3, 1, 23.68, 0)
R(current_mirror_ota_0, met4, [(11.25,-0.165,12.43,0.165), (34.93,-0.165,36.11,0.165), (11.25,17.475,12.43,17.805), (34.93,17.475,36.11,17.805)])
R(current_mirror_ota_0, L104_0, [(-4,-4,57.91,25.59)])
R(current_mirror_ota_0, L235_5, [(0,0,53.91,21.59)])
current_mirror_ota_0.add(gdstk.Reference(dcl_nmos_s_8415993_x1_y1, (26.66,7.56), rotation=pi, x_reflection=True))
current_mirror_ota_0.add(gdstk.Reference(dcl_nmos_s_91990922_x14_, (35.26,13.44)))
current_mirror_ota_0.add(gdstk.Reference(dcl_pmos_s_18488141_x5_y, (24.08,13.44), rotation=pi, x_reflection=True))
current_mirror_ota_0.add(gdstk.Reference(dcl_pmos_s_18488141_x5_y, (29.24,13.44)))
current_mirror_ota_0.add(gdstk.Reference(nmos_s_70322697_x14_y1_1, (18.06,13.44), rotation=pi, x_reflection=True))
current_mirror_ota_0.add(gdstk.Reference(nmos_s_73503000_x1_y1_17, (26.66,7.56)))
current_mirror_ota_0.add(gdstk.Reference(pmos_s_55784090_x26_y2_1, (29.24,13.44), x_reflection=True))
current_mirror_ota_0.add(gdstk.Reference(pmos_s_55784090_x26_y2_1, (24.08,13.44), rotation=pi))
current_mirror_ota_0.add(gdstk.Reference(nmos_4t_9061234_x1_y1_17, (24.08,7.56), x_reflection=True))
current_mirror_ota_0.add(gdstk.Reference(nmos_4t_9061234_x1_y1_17, (29.24,7.56), rotation=pi))
current_mirror_ota_0.add(gdstk.Label('ID', (25.37,10.08), layer=69, texttype=5))
current_mirror_ota_0.add(gdstk.Label('VOUT', (12.47,10.08), layer=69, texttype=5))
current_mirror_ota_0.add(gdstk.Label('VINN', (24.94,2.94), layer=68, texttype=5))
current_mirror_ota_0.add(gdstk.Label('VINP', (28.38,2.94), layer=68, texttype=5))
current_mirror_ota_0.add(gdstk.Label('VSS', (23.68,13.23), layer=71, texttype=5))
current_mirror_ota_0.add(gdstk.Label('VSS', (23.68,13.23), layer=71, texttype=5))
current_mirror_ota_0.add(gdstk.Label('VSS', (23.68,13.23), layer=71, texttype=5))
current_mirror_ota_0.add(gdstk.Label('VSS', (42.785,14.7), layer=68, texttype=5))
current_mirror_ota_0.add(gdstk.Label('VSS', (23.68,13.23), layer=71, texttype=5))
current_mirror_ota_0.add(gdstk.Label('VSS', (23.68,13.23), layer=71, texttype=5))
current_mirror_ota_0.add(gdstk.Label('VSS', (23.68,13.23), layer=71, texttype=5))
current_mirror_ota_0.add(gdstk.Label('VSS', (23.68,13.23), layer=71, texttype=5))
current_mirror_ota_0.add(gdstk.Label('VSS', (23.68,13.23), layer=71, texttype=5))
current_mirror_ota_0.add(gdstk.Label('VSS', (23.68,13.23), layer=71, texttype=5))
current_mirror_ota_0.add(gdstk.Label('VSS', (23.68,13.23), layer=71, texttype=5))
current_mirror_ota_0.add(gdstk.Label('VSS', (23.68,13.23), layer=71, texttype=5))
current_mirror_ota_0.add(gdstk.Label('VSS', (23.68,13.23), layer=71, texttype=5))
current_mirror_ota_0.add(gdstk.Label('VSS', (23.68,13.23), layer=71, texttype=5))
current_mirror_ota_0.add(gdstk.Label('VSS', (23.68,13.23), layer=71, texttype=5))
current_mirror_ota_0.add(gdstk.Label('VSS', (23.68,13.23), layer=71, texttype=5))
current_mirror_ota_0.add(gdstk.Label('VSS', (23.68,13.23), layer=71, texttype=5))
current_mirror_ota_0.add(gdstk.Label('VSS', (23.68,13.23), layer=71, texttype=5))
current_mirror_ota_0.add(gdstk.Label('VSS', (23.68,13.23), layer=71, texttype=5))
current_mirror_ota_0.add(gdstk.Label('VDD', (35.52,13.23), layer=71, texttype=5))
current_mirror_ota_0.add(gdstk.Label('VDD', (35.52,13.23), layer=71, texttype=5))
current_mirror_ota_0.add(gdstk.Label('VDD', (35.52,13.23), layer=71, texttype=5))
current_mirror_ota_0.add(gdstk.Label('VDD', (35.52,13.23), layer=71, texttype=5))
current_mirror_ota_0.add(gdstk.Label('VDD', (41.71,0.63), layer=69, texttype=5))
current_mirror_ota_0.add(gdstk.Label('VDD', (35.52,13.23), layer=71, texttype=5))
current_mirror_ota_0.add(gdstk.Label('VDD', (35.52,13.23), layer=71, texttype=5))
current_mirror_ota_0.add(gdstk.Label('VDD', (35.52,13.23), layer=71, texttype=5))
current_mirror_ota_0.add(gdstk.Label('VDD', (35.52,13.23), layer=71, texttype=5))
current_mirror_ota_0.add(gdstk.Label('VDD', (35.52,13.23), layer=71, texttype=5))
current_mirror_ota_0.add(gdstk.Label('VDD', (35.52,13.23), layer=71, texttype=5))
current_mirror_ota_0.add(gdstk.Label('VDD', (35.52,13.23), layer=71, texttype=5))
current_mirror_ota_0.add(gdstk.Label('VDD', (35.52,13.23), layer=71, texttype=5))

lib.write_gds('CURRENT_MIRROR_OTA_0.gds')
